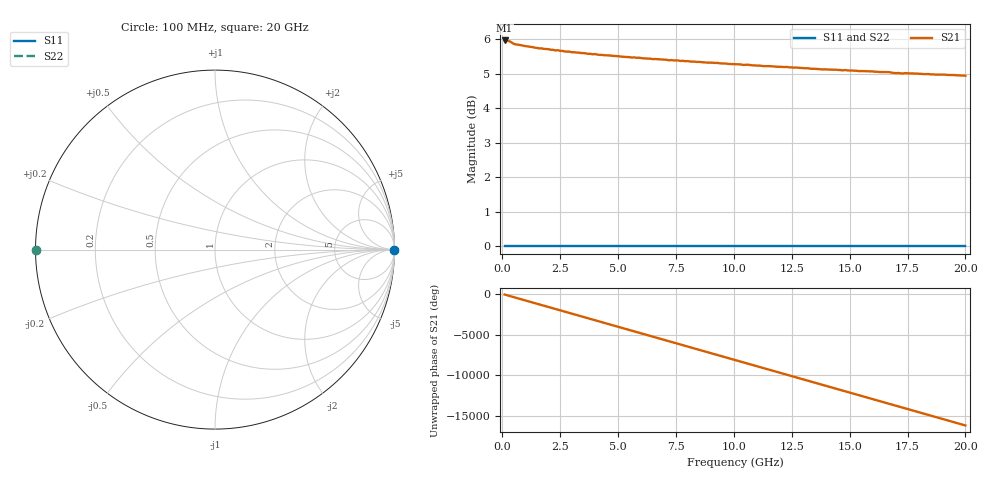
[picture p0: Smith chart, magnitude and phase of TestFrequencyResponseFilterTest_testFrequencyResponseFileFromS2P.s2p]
! File created by SignalIntegrity v1.5.4: Signal and Power Integrity Tools
! https://github.com/Nubis-Communications/SignalIntegrity
# MHz S MA R 50.0
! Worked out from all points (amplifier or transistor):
!   200 points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, 100 MHz to 20 GHz, reference 50 ohm
!   highest |S21| = 6.0 dB at 100 MHz (marker M1)
!   |S21| within 3 dB of that: start of sweep to end of sweep
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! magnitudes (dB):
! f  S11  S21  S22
! 100 MHz  0.0  6.0  0.0
! 300 MHz  0.0  5.9  0.0
! 500 MHz  0.0  5.9  0.0
! 1.6 GHz  0.0  5.7  0.0
! 2.3 GHz  0.0  5.7  0.0
! 2.4 GHz  0.0  5.7  0.0
! 3 GHz  0.0  5.6  0.0
! 3.5 GHz  0.0  5.6  0.0
! 3.9 GHz  0.0  5.6  0.0
! 4 GHz  0.0  5.6  0.0
! 4.2 GHz  0.0  5.5  0.0
! 6.8 GHz  0.0  5.4  0.0
! 10.1 GHz  0.0  5.3  0.0
! 11.3 GHz  0.0  5.2  0.0
! 12.3 GHz  0.0  5.2  0.0
! 13.4 GHz  0.0  5.1  0.0
! 13.8 GHz  0.0  5.1  0.0
! 14.4 GHz  0.0  5.1  0.0
! 16.7 GHz  0.0  5.0  0.0
! 17.3 GHz  0.0  5.0  0.0
! 17.4 GHz  0.0  5.0  0.0
! 20 GHz  0.0  4.9  0.0
